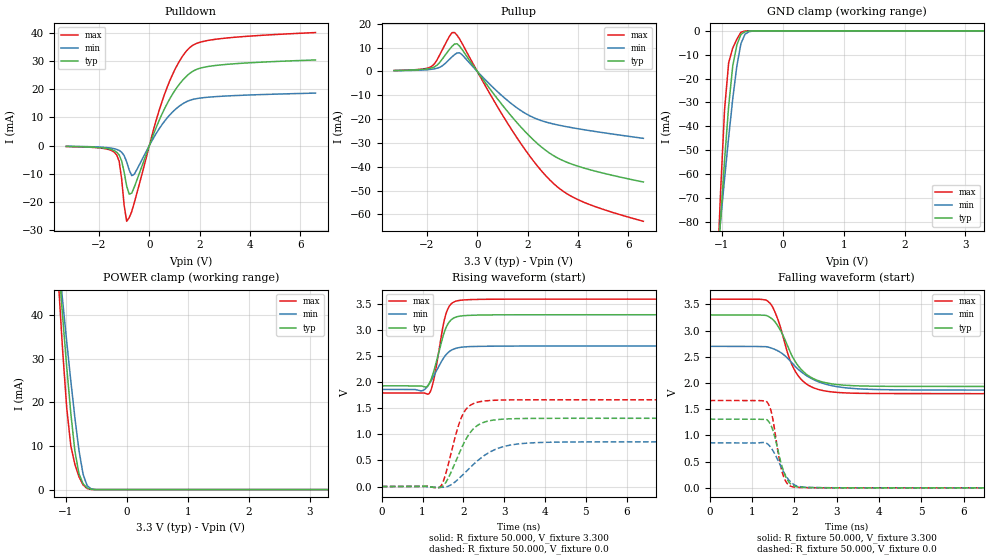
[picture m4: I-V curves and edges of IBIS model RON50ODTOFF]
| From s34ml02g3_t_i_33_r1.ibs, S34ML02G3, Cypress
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|   Model RON50ODTOFF
[Model] RON50ODTOFF
Model_type I/O
Polarity   Non-Inverting
Enable   Active-High
Vinl =  0.660V
Vinh =  2.640V
Vmeas =  1.650V
Cref =  2.000pF
Rref =  50.000
Vref =  1.650V
C_comp   2.860pF   2.840pF   2.890pF
[Model Spec]
Vinh   2.640V   2.160V   2.880V
Vinl   0.660V   0.540V   0.720V
Vmeas   1.650V   1.350V   1.800V
Vref   1.650V   1.350V   1.800V
Cref   2.000pF   NA   NA
Rref   50.000   NA   NA
[Temperature Range]   25.000   85.000   -40.000
[Voltage Range]   3.300V   2.700V   3.600V
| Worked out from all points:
|   slope of the pulldown table from 0 to 0.495 V, typ, clamps not added: 44.7 ohm
|   slope of the pullup table from 0 to 0.495 V, typ, clamps not added: 68.6 ohm
|   GND clamp passes 1 mA (typ) near -0.66 V on its own axis
|   POWER clamp passes 1 mA (typ) near -0.70 V on its own axis
|   rising waveform, R_fixture 50.000, V_fixture 3.300: 20-80 % time 289ps typ, 366ps min, 243ps max; typ from 1.93 V to 3.3 V
|   rising waveform, R_fixture 50.000, V_fixture 0.0: 20-80 % time 488ps typ, 794ps min, 356ps max; typ from 0 V to 1.31 V
|   falling waveform, R_fixture 50.000, V_fixture 3.300: 20-80 % time 569ps typ, 784ps min, 474ps max; typ from 3.3 V to 1.93 V
|   falling waveform, R_fixture 50.000, V_fixture 0.0: 20-80 % time 258ps typ, 339ps min, 214ps max; typ from 1.31 V to 0 V
[Pulldown]
|Voltage   I(typ)   I(min)   I(max)
-3.3V     -314.4uA   -244.3uA   -343.9uA
-1.3V     -2.313mA   -1.345mA   -3.287mA
-1.2V     -3.323mA   -1.722mA   -5.561mA
-1V       -9.524mA   -3.588mA   -21.38mA
-900mV    -14.44mA   -5.819mA   -26.96mA
-800mV    -17.32mA   -8.724mA   -25.66mA
-600mV    -14.83mA   -10.21mA   -20.4mA
600mV     13.04mA    8.625mA    18.17mA
1.1V      20.72mA    13.4mA     28.53mA
1.6V      25.66mA    16.08mA    34.84mA
2.8V      28.68mA    17.52mA    38.03mA
6.6V      30.48mA    18.68mA    40.23mA
[Pullup]
|Voltage   I(typ)   I(min)   I(max)
-3.3V     361.6uA    283.6uA    389.8uA
-1.8V     1.488mA    919.1uA    2.182mA
-1.5V     3.655mA    1.683mA    6.756mA
-1.1V     9.273mA    5.12mA     14.81mA
-900mV    11.5mA     7.05mA     16.29mA
-600mV    9.149mA    6.964mA    11.69mA
500mV     -7.287mA   -5.429mA   -9.361mA
1.4V      -19.33mA   -13.9mA    -25mA
2.1V      -27.4mA    -18.71mA   -35.74mA
2.9V      -34.48mA   -21.74mA   -45.73mA
4.1V      -40.11mA   -24.23mA   -54.29mA
6.6V      -46.43mA   -28.1mA    -62.9mA
[GND_clamp]
|Voltage   I(typ)   I(min)   I(max)
-3.3V     -1.091A    -761mA     -1.739A
-1.089V   -106.4mA   -98.63mA   -110mA
-1.022V   -79.54mA   -80.06mA   -68.12mA
-955mV    -54.15mA   -61.98mA   -32.91mA
-888mV    -31.54mA   -44.64mA   -13.37mA
-821mV    -14.71mA   -28.56mA   -7.248mA
-754mV    -5.951mA   -14.81mA   -3.53mA
-687mV    -1.508mA   -5.409mA   -606.1uA
-620mV    -369.5uA   -1.421mA   -79.63uA
-553mV    -79.73uA   -350.6uA   -8.879uA
-486mV    -14.59uA   -85.42uA   -793.1nA
3.3V      0A         0A         0A
[POWER_clamp]
|Voltage   I(typ)   I(min)   I(max)
-3.3V     484mA      387mA      621.1mA
-1.122V   51.69mA    52.79mA    47mA
-1.055V   39.6mA     43.22mA    31.83mA
-988mV    28.05mA    33.88mA    18.67mA
-921mV    17.46mA    24.87mA    10.02mA
-854mV    8.817mA    16.42mA    5.78mA
-787mV    3.61mA     8.999mA    2.955mA
-720mV    1.342mA    3.534mA    1.088mA
-653mV    380.8uA    901.7uA    235uA
-586mV    72.64uA    176uA      28.35uA
-452mV    1.393uA    5.4uA      201.2nA
3.3V      0A         0A         3.891nA
[Ramp]
| variable   typ   min   max
dV/dt_r   0.787/0.489n   0.515/0.796n   1.000/0.357n
dV/dt_f   0.819/0.569n   0.501/0.783n   1.081/0.474n
R_load = 50.000
| The next line is not an IBIS keyword
| [Initial Delay]   1.100ns   1.900ns   0.430ns
[Rising Waveform]
R_fixture= 50.000
V_fixture= 3.300
V_fixture_min= 2.700
V_fixture_max= 3.600
|time   V(typ)   V(min)   V(max)
0s        1.934V     1.865V     1.798V
981ps     1.931V     1.84V      1.799V
1.163ns   1.974V     1.973V     1.789V
1.216ns   2.072V     2.041V     1.876V
1.287ns   2.247V     2.141V     2.099V
1.485ns   2.846V     2.432V     3.016V
1.583ns   3.066V     2.54V      3.342V
1.712ns   3.209V     2.622V     3.516V
1.945ns   3.277V     2.675V     3.58V
19.57ns   3.3V       2.7V       3.6V
[Rising Waveform]
R_fixture= 50.000
V_fixture= 0.0
V_fixture_min= 0.0
V_fixture_max= 0.0
|time   V(typ)   V(min)   V(max)
0s        -3.199nV   -1.773uV   11.18nV
1.42ns    -19.73mV   -15.77mV   -10.75mV
1.607ns   127.8mV    -292.9uV   356.3mV
1.847ns   549mV      122.1mV    1.089V
1.997ns   809.9mV    234.2mV    1.402V
2.238ns   1.103V     419.4mV    1.59V
2.538ns   1.243V     609.1mV    1.645V
3.127ns   1.3V       792.9mV    1.664V
4.148ns   1.31V      851.3mV    1.666V
19.57ns   1.311V     858.5mV    1.666V
[Falling Waveform]
R_fixture= 50.000
V_fixture= 3.300
V_fixture_min= 2.700
V_fixture_max= 3.600
|time   V(typ)   V(min)   V(max)
0s        3.3V       2.7V       3.6V
1.361ns   3.282V     2.69V      3.567V
1.556ns   3.154V     2.636V     3.328V
1.721ns   2.93V      2.558V     2.924V
1.885ns   2.621V     2.436V     2.467V
2.081ns   2.339V     2.269V     2.149V
2.377ns   2.116V     2.097V     1.937V
2.865ns   1.986V     1.953V     1.832V
4.567ns   1.935V     1.869V     1.798V
19.57ns   1.934V     1.865V     1.798V
[Falling Waveform]
R_fixture= 50.000
V_fixture= 0.0
V_fixture_min= 0.0
V_fixture_max= 0.0
|time   V(typ)   V(min)   V(max)
0s        1.311V     858.5mV    1.666V
1.346ns   1.302V     850mV      1.645V
1.466ns   1.158V     745.6mV    1.417V
1.536ns   980.5mV    650.7mV    1.1V
1.644ns   608.5mV    474mV      544.8mV
1.736ns   339.2mV    320.8mV    238.4mV
1.845ns   141.3mV    176.7mV    69.26mV
2.016ns   28.18mV    52.03mV    13.43mV
3.013ns   1.146mV    1.81mV     729uV
19.57ns   8.306nV    14.01nV    10.85nV
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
